VERSION 5.7 ;
  NOWIREEXTENSIONATPIN ON ;
  DIVIDERCHAR "/" ;
  BUSBITCHARS "[]" ;
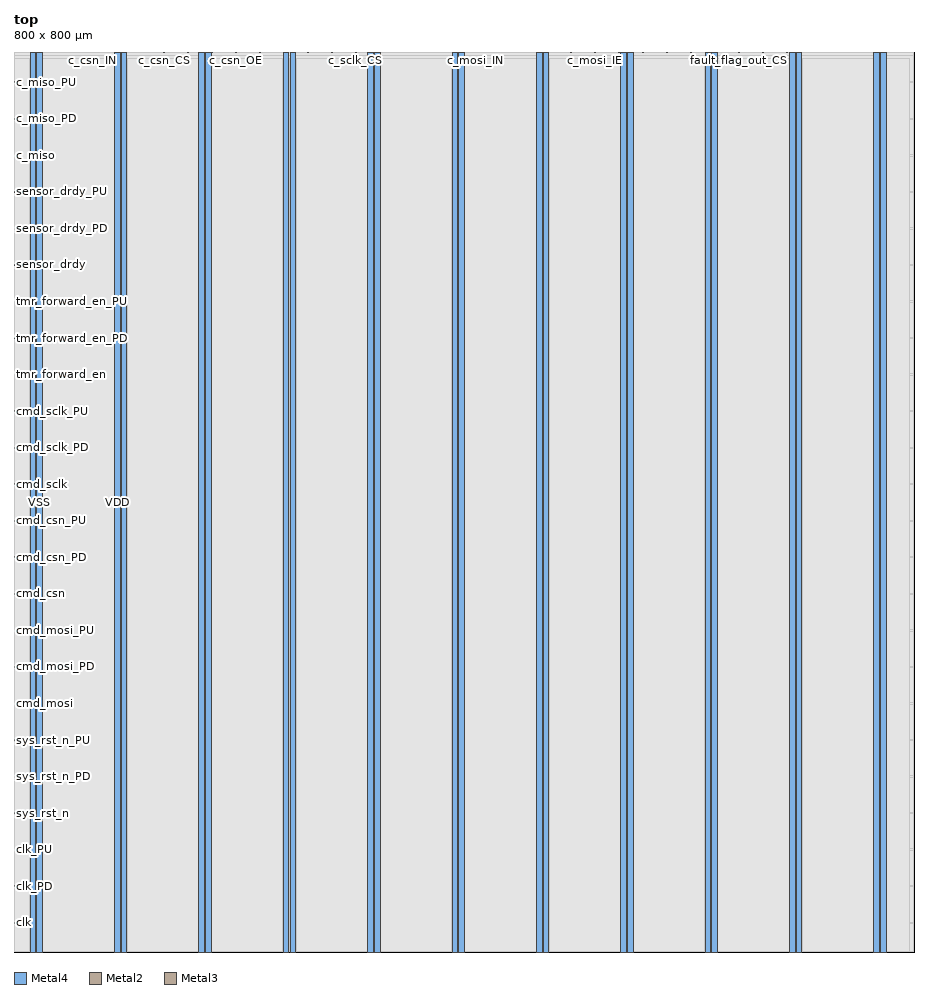
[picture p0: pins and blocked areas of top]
MACRO top
  CLASS BLOCK ;
  FOREIGN top ;
  ORIGIN 0.000 0.000 ;
  SIZE 800.000 BY 800.000 ;
  PIN VDD
    DIRECTION INOUT ;
    USE POWER ;
    PORT
      LAYER Metal4 ;
        RECT 14.380 0.000 19.380 800.000 ;
    END
    PORT
      LAYER Metal4 ;
        RECT 89.380 0.000 94.380 800.000 ;
    END
    PORT
      LAYER Metal4 ;
        RECT 164.380 0.000 169.380 800.000 ;
    END
    PORT
      LAYER Metal4 ;
        RECT 239.380 0.000 244.380 800.000 ;
    END
    PORT
      LAYER Metal4 ;
        RECT 314.380 0.000 319.380 800.000 ;
    END
    PORT
      LAYER Metal4 ;
        RECT 389.380 0.000 394.380 800.000 ;
    END
    PORT
      LAYER Metal4 ;
        RECT 464.380 0.000 469.380 800.000 ;
    END
    PORT
      LAYER Metal4 ;
        RECT 539.380 0.000 544.380 800.000 ;
    END
    PORT
      LAYER Metal4 ;
        RECT 614.380 0.000 619.380 800.000 ;
    END
    PORT
      LAYER Metal4 ;
        RECT 689.380 0.000 694.380 800.000 ;
    END
    PORT
      LAYER Metal4 ;
        RECT 764.380 0.000 769.380 800.000 ;
    END
  END VDD
  PIN VSS
    DIRECTION INOUT ;
    USE GROUND ;
    PORT
      LAYER Metal4 ;
        RECT 20.380 0.000 25.380 800.000 ;
    END
    PORT
      LAYER Metal4 ;
        RECT 95.380 0.000 100.380 800.000 ;
    END
    PORT
      LAYER Metal4 ;
        RECT 170.380 0.000 175.380 800.000 ;
    END
    PORT
      LAYER Metal4 ;
        RECT 245.380 0.000 250.380 800.000 ;
    END
    PORT
      LAYER Metal4 ;
        RECT 320.380 0.000 325.380 800.000 ;
    END
    PORT
      LAYER Metal4 ;
        RECT 395.380 0.000 400.380 800.000 ;
    END
    PORT
      LAYER Metal4 ;
        RECT 470.380 0.000 475.380 800.000 ;
    END
    PORT
      LAYER Metal4 ;
        RECT 545.380 0.000 550.380 800.000 ;
    END
    PORT
      LAYER Metal4 ;
        RECT 620.380 0.000 625.380 800.000 ;
    END
    PORT
      LAYER Metal4 ;
        RECT 695.380 0.000 700.380 800.000 ;
    END
    PORT
      LAYER Metal4 ;
        RECT 770.380 0.000 775.380 800.000 ;
    END
  END VSS
  PIN c_csn_CS
    DIRECTION OUTPUT ;
    USE SIGNAL ;
    ANTENNADIFFAREA 0.360800 ;
    PORT
      LAYER Metal2 ;
        RECT 133.280 799.440 133.840 800.000 ;
    END
  END c_csn_CS
  PIN c_csn_IE
    DIRECTION OUTPUT ;
    USE SIGNAL ;
    ANTENNADIFFAREA 0.360800 ;
    PORT
      LAYER Metal2 ;
        RECT 175.840 799.440 176.400 800.000 ;
    END
  END c_csn_IE
  PIN c_csn_IN
    DIRECTION INPUT ;
    USE SIGNAL ;
    PORT
      LAYER Metal2 ;
        RECT 69.440 799.440 70.000 800.000 ;
    END
  END c_csn_IN
  PIN c_csn_OE
    DIRECTION OUTPUT ;
    USE SIGNAL ;
    ANTENNADIFFAREA 0.536800 ;
    PORT
      LAYER Metal2 ;
        RECT 197.120 799.440 197.680 800.000 ;
    END
  END c_csn_OE
  PIN c_csn_OUT
    DIRECTION OUTPUT ;
    USE SIGNAL ;
    ANTENNADIFFAREA 0.897600 ;
    PORT
      LAYER Metal2 ;
        RECT 48.160 799.440 48.720 800.000 ;
    END
  END c_csn_OUT
  PIN c_csn_PD
    DIRECTION OUTPUT ;
    USE SIGNAL ;
    ANTENNADIFFAREA 0.360800 ;
    PORT
      LAYER Metal2 ;
        RECT 90.720 799.440 91.280 800.000 ;
    END
  END c_csn_PD
  PIN c_csn_PU
    DIRECTION OUTPUT ;
    USE SIGNAL ;
    ANTENNADIFFAREA 0.536800 ;
    PORT
      LAYER Metal2 ;
        RECT 112.000 799.440 112.560 800.000 ;
    END
  END c_csn_PU
  PIN c_csn_SL
    DIRECTION OUTPUT ;
    USE SIGNAL ;
    ANTENNADIFFAREA 0.360800 ;
    PORT
      LAYER Metal2 ;
        RECT 154.560 799.440 155.120 800.000 ;
    END
  END c_csn_SL
  PIN c_miso
    DIRECTION INPUT ;
    USE SIGNAL ;
    ANTENNAGATEAREA 0.396000 ;
    ANTENNADIFFAREA 0.410400 ;
    PORT
      LAYER Metal3 ;
        RECT 0.000 707.840 0.560 708.400 ;
    END
  END c_miso
  PIN c_miso_PD
    DIRECTION OUTPUT ;
    USE SIGNAL ;
    ANTENNADIFFAREA 0.360800 ;
    PORT
      LAYER Metal3 ;
        RECT 0.000 740.320 0.560 740.880 ;
    END
  END c_miso_PD
  PIN c_miso_PU
    DIRECTION OUTPUT ;
    USE SIGNAL ;
    ANTENNADIFFAREA 0.360800 ;
    PORT
      LAYER Metal3 ;
        RECT 0.000 772.800 0.560 773.360 ;
    END
  END c_miso_PU
  PIN c_mosi_CS
    DIRECTION OUTPUT ;
    USE SIGNAL ;
    ANTENNADIFFAREA 0.360800 ;
    PORT
      LAYER Metal2 ;
        RECT 473.760 799.440 474.320 800.000 ;
    END
  END c_mosi_CS
  PIN c_mosi_IE
    DIRECTION OUTPUT ;
    USE SIGNAL ;
    ANTENNADIFFAREA 0.360800 ;
    PORT
      LAYER Metal2 ;
        RECT 516.320 799.440 516.880 800.000 ;
    END
  END c_mosi_IE
  PIN c_mosi_IN
    DIRECTION INPUT ;
    USE SIGNAL ;
    PORT
      LAYER Metal2 ;
        RECT 409.920 799.440 410.480 800.000 ;
    END
  END c_mosi_IN
  PIN c_mosi_OE
    DIRECTION OUTPUT ;
    USE SIGNAL ;
    ANTENNADIFFAREA 0.536800 ;
    PORT
      LAYER Metal2 ;
        RECT 537.600 799.440 538.160 800.000 ;
    END
  END c_mosi_OE
  PIN c_mosi_OUT
    DIRECTION OUTPUT ;
    USE SIGNAL ;
    ANTENNADIFFAREA 0.897600 ;
    PORT
      LAYER Metal2 ;
        RECT 388.640 799.440 389.200 800.000 ;
    END
  END c_mosi_OUT
  PIN c_mosi_PD
    DIRECTION OUTPUT ;
    USE SIGNAL ;
    ANTENNADIFFAREA 0.360800 ;
    PORT
      LAYER Metal2 ;
        RECT 431.200 799.440 431.760 800.000 ;
    END
  END c_mosi_PD
  PIN c_mosi_PU
    DIRECTION OUTPUT ;
    USE SIGNAL ;
    ANTENNADIFFAREA 0.360800 ;
    PORT
      LAYER Metal2 ;
        RECT 452.480 799.440 453.040 800.000 ;
    END
  END c_mosi_PU
  PIN c_mosi_SL
    DIRECTION OUTPUT ;
    USE SIGNAL ;
    ANTENNADIFFAREA 0.360800 ;
    PORT
      LAYER Metal2 ;
        RECT 495.040 799.440 495.600 800.000 ;
    END
  END c_mosi_SL
  PIN c_sclk_CS
    DIRECTION OUTPUT ;
    USE SIGNAL ;
    ANTENNADIFFAREA 0.360800 ;
    PORT
      LAYER Metal2 ;
        RECT 303.520 799.440 304.080 800.000 ;
    END
  END c_sclk_CS
  PIN c_sclk_IE
    DIRECTION OUTPUT ;
    USE SIGNAL ;
    ANTENNADIFFAREA 0.360800 ;
    PORT
      LAYER Metal2 ;
        RECT 346.080 799.440 346.640 800.000 ;
    END
  END c_sclk_IE
  PIN c_sclk_IN
    DIRECTION INPUT ;
    USE SIGNAL ;
    PORT
      LAYER Metal2 ;
        RECT 239.680 799.440 240.240 800.000 ;
    END
  END c_sclk_IN
  PIN c_sclk_OE
    DIRECTION OUTPUT ;
    USE SIGNAL ;
    ANTENNADIFFAREA 0.536800 ;
    PORT
      LAYER Metal2 ;
        RECT 367.360 799.440 367.920 800.000 ;
    END
  END c_sclk_OE
  PIN c_sclk_OUT
    DIRECTION OUTPUT ;
    USE SIGNAL ;
    ANTENNADIFFAREA 0.897600 ;
    PORT
      LAYER Metal2 ;
        RECT 218.400 799.440 218.960 800.000 ;
    END
  END c_sclk_OUT
  PIN c_sclk_PD
    DIRECTION OUTPUT ;
    USE SIGNAL ;
    ANTENNADIFFAREA 0.360800 ;
    PORT
      LAYER Metal2 ;
        RECT 260.960 799.440 261.520 800.000 ;
    END
  END c_sclk_PD
  PIN c_sclk_PU
    DIRECTION OUTPUT ;
    USE SIGNAL ;
    ANTENNADIFFAREA 0.360800 ;
    PORT
      LAYER Metal2 ;
        RECT 282.240 799.440 282.800 800.000 ;
    END
  END c_sclk_PU
  PIN c_sclk_SL
    DIRECTION OUTPUT ;
    USE SIGNAL ;
    ANTENNADIFFAREA 0.360800 ;
    PORT
      LAYER Metal2 ;
        RECT 324.800 799.440 325.360 800.000 ;
    END
  END c_sclk_SL
  PIN clk
    DIRECTION INPUT ;
    USE SIGNAL ;
    ANTENNAGATEAREA 4.738000 ;
    ANTENNADIFFAREA 0.410400 ;
    PORT
      LAYER Metal3 ;
        RECT 0.000 25.760 0.560 26.320 ;
    END
  END clk
  PIN clk_PD
    DIRECTION OUTPUT ;
    USE SIGNAL ;
    ANTENNADIFFAREA 0.360800 ;
    PORT
      LAYER Metal3 ;
        RECT 0.000 58.240 0.560 58.800 ;
    END
  END clk_PD
  PIN clk_PU
    DIRECTION OUTPUT ;
    USE SIGNAL ;
    ANTENNADIFFAREA 0.360800 ;
    PORT
      LAYER Metal3 ;
        RECT 0.000 90.720 0.560 91.280 ;
    END
  END clk_PU
  PIN cmd_csn
    DIRECTION INPUT ;
    USE SIGNAL ;
    ANTENNAGATEAREA 0.396000 ;
    ANTENNADIFFAREA 0.410400 ;
    PORT
      LAYER Metal3 ;
        RECT 0.000 318.080 0.560 318.640 ;
    END
  END cmd_csn
  PIN cmd_csn_PD
    DIRECTION OUTPUT ;
    USE SIGNAL ;
    ANTENNADIFFAREA 0.360800 ;
    PORT
      LAYER Metal3 ;
        RECT 0.000 350.560 0.560 351.120 ;
    END
  END cmd_csn_PD
  PIN cmd_csn_PU
    DIRECTION OUTPUT ;
    USE SIGNAL ;
    ANTENNADIFFAREA 0.360800 ;
    PORT
      LAYER Metal3 ;
        RECT 0.000 383.040 0.560 383.600 ;
    END
  END cmd_csn_PU
  PIN cmd_mosi
    DIRECTION INPUT ;
    USE SIGNAL ;
    ANTENNAGATEAREA 0.396000 ;
    ANTENNADIFFAREA 0.410400 ;
    PORT
      LAYER Metal3 ;
        RECT 0.000 220.640 0.560 221.200 ;
    END
  END cmd_mosi
  PIN cmd_mosi_PD
    DIRECTION OUTPUT ;
    USE SIGNAL ;
    ANTENNADIFFAREA 0.360800 ;
    PORT
      LAYER Metal3 ;
        RECT 0.000 253.120 0.560 253.680 ;
    END
  END cmd_mosi_PD
  PIN cmd_mosi_PU
    DIRECTION OUTPUT ;
    USE SIGNAL ;
    ANTENNADIFFAREA 0.360800 ;
    PORT
      LAYER Metal3 ;
        RECT 0.000 285.600 0.560 286.160 ;
    END
  END cmd_mosi_PU
  PIN cmd_sclk
    DIRECTION INPUT ;
    USE SIGNAL ;
    ANTENNAGATEAREA 0.396000 ;
    ANTENNADIFFAREA 0.410400 ;
    PORT
      LAYER Metal3 ;
        RECT 0.000 415.520 0.560 416.080 ;
    END
  END cmd_sclk
  PIN cmd_sclk_PD
    DIRECTION OUTPUT ;
    USE SIGNAL ;
    ANTENNADIFFAREA 0.360800 ;
    PORT
      LAYER Metal3 ;
        RECT 0.000 448.000 0.560 448.560 ;
    END
  END cmd_sclk_PD
  PIN cmd_sclk_PU
    DIRECTION OUTPUT ;
    USE SIGNAL ;
    ANTENNADIFFAREA 0.360800 ;
    PORT
      LAYER Metal3 ;
        RECT 0.000 480.480 0.560 481.040 ;
    END
  END cmd_sclk_PU
  PIN fault_flag_out_CS
    DIRECTION OUTPUT ;
    USE SIGNAL ;
    ANTENNADIFFAREA 0.360800 ;
    PORT
      LAYER Metal2 ;
        RECT 644.000 799.440 644.560 800.000 ;
    END
  END fault_flag_out_CS
  PIN fault_flag_out_IE
    DIRECTION OUTPUT ;
    USE SIGNAL ;
    ANTENNADIFFAREA 0.360800 ;
    PORT
      LAYER Metal2 ;
        RECT 686.560 799.440 687.120 800.000 ;
    END
  END fault_flag_out_IE
  PIN fault_flag_out_IN
    DIRECTION INPUT ;
    USE SIGNAL ;
    PORT
      LAYER Metal2 ;
        RECT 580.160 799.440 580.720 800.000 ;
    END
  END fault_flag_out_IN
  PIN fault_flag_out_OE
    DIRECTION OUTPUT ;
    USE SIGNAL ;
    ANTENNADIFFAREA 0.536800 ;
    PORT
      LAYER Metal2 ;
        RECT 707.840 799.440 708.400 800.000 ;
    END
  END fault_flag_out_OE
  PIN fault_flag_out_OUT
    DIRECTION OUTPUT ;
    USE SIGNAL ;
    ANTENNADIFFAREA 0.897600 ;
    PORT
      LAYER Metal2 ;
        RECT 558.880 799.440 559.440 800.000 ;
    END
  END fault_flag_out_OUT
  PIN fault_flag_out_PD
    DIRECTION OUTPUT ;
    USE SIGNAL ;
    ANTENNADIFFAREA 0.360800 ;
    PORT
      LAYER Metal2 ;
        RECT 601.440 799.440 602.000 800.000 ;
    END
  END fault_flag_out_PD
  PIN fault_flag_out_PU
    DIRECTION OUTPUT ;
    USE SIGNAL ;
    ANTENNADIFFAREA 0.360800 ;
    PORT
      LAYER Metal2 ;
        RECT 622.720 799.440 623.280 800.000 ;
    END
  END fault_flag_out_PU
  PIN fault_flag_out_SL
    DIRECTION OUTPUT ;
    USE SIGNAL ;
    ANTENNADIFFAREA 0.360800 ;
    PORT
      LAYER Metal2 ;
        RECT 665.280 799.440 665.840 800.000 ;
    END
  END fault_flag_out_SL
  PIN sensor_drdy
    DIRECTION INPUT ;
    USE SIGNAL ;
    ANTENNAGATEAREA 0.396000 ;
    ANTENNADIFFAREA 0.410400 ;
    PORT
      LAYER Metal3 ;
        RECT 0.000 610.400 0.560 610.960 ;
    END
  END sensor_drdy
  PIN sensor_drdy_PD
    DIRECTION OUTPUT ;
    USE SIGNAL ;
    ANTENNADIFFAREA 0.360800 ;
    PORT
      LAYER Metal3 ;
        RECT 0.000 642.880 0.560 643.440 ;
    END
  END sensor_drdy_PD
  PIN sensor_drdy_PU
    DIRECTION OUTPUT ;
    USE SIGNAL ;
    ANTENNADIFFAREA 0.360800 ;
    PORT
      LAYER Metal3 ;
        RECT 0.000 675.360 0.560 675.920 ;
    END
  END sensor_drdy_PU
  PIN sys_rst_n
    DIRECTION INPUT ;
    USE SIGNAL ;
    ANTENNAGATEAREA 0.396000 ;
    ANTENNADIFFAREA 0.410400 ;
    PORT
      LAYER Metal3 ;
        RECT 0.000 123.200 0.560 123.760 ;
    END
  END sys_rst_n
  PIN sys_rst_n_PD
    DIRECTION OUTPUT ;
    USE SIGNAL ;
    ANTENNADIFFAREA 0.360800 ;
    PORT
      LAYER Metal3 ;
        RECT 0.000 155.680 0.560 156.240 ;
    END
  END sys_rst_n_PD
  PIN sys_rst_n_PU
    DIRECTION OUTPUT ;
    USE SIGNAL ;
    ANTENNADIFFAREA 0.360800 ;
    PORT
      LAYER Metal3 ;
        RECT 0.000 188.160 0.560 188.720 ;
    END
  END sys_rst_n_PU
  PIN tmr_forward_en
    DIRECTION INPUT ;
    USE SIGNAL ;
    ANTENNAGATEAREA 0.396000 ;
    ANTENNADIFFAREA 0.410400 ;
    PORT
      LAYER Metal3 ;
        RECT 0.000 512.960 0.560 513.520 ;
    END
  END tmr_forward_en
  PIN tmr_forward_en_PD
    DIRECTION OUTPUT ;
    USE SIGNAL ;
    ANTENNADIFFAREA 0.360800 ;
    PORT
      LAYER Metal3 ;
        RECT 0.000 545.440 0.560 546.000 ;
    END
  END tmr_forward_en_PD
  PIN tmr_forward_en_PU
    DIRECTION OUTPUT ;
    USE SIGNAL ;
    ANTENNADIFFAREA 0.360800 ;
    PORT
      LAYER Metal3 ;
        RECT 0.000 577.920 0.560 578.480 ;
    END
  END tmr_forward_en_PU
  OBS
      LAYER Nwell ;
        RECT 0.130 3.490 799.550 796.190 ;
      LAYER Metal1 ;
        RECT 0.560 3.620 799.120 796.060 ;
      LAYER Metal2 ;
        RECT 0.140 799.140 47.860 799.860 ;
        RECT 49.020 799.140 69.140 799.860 ;
        RECT 70.300 799.140 90.420 799.860 ;
        RECT 91.580 799.140 111.700 799.860 ;
        RECT 112.860 799.140 132.980 799.860 ;
        RECT 134.140 799.140 154.260 799.860 ;
        RECT 155.420 799.140 175.540 799.860 ;
        RECT 176.700 799.140 196.820 799.860 ;
        RECT 197.980 799.140 218.100 799.860 ;
        RECT 219.260 799.140 239.380 799.860 ;
        RECT 240.540 799.140 260.660 799.860 ;
        RECT 261.820 799.140 281.940 799.860 ;
        RECT 283.100 799.140 303.220 799.860 ;
        RECT 304.380 799.140 324.500 799.860 ;
        RECT 325.660 799.140 345.780 799.860 ;
        RECT 346.940 799.140 367.060 799.860 ;
        RECT 368.220 799.140 388.340 799.860 ;
        RECT 389.500 799.140 409.620 799.860 ;
        RECT 410.780 799.140 430.900 799.860 ;
        RECT 432.060 799.140 452.180 799.860 ;
        RECT 453.340 799.140 473.460 799.860 ;
        RECT 474.620 799.140 494.740 799.860 ;
        RECT 495.900 799.140 516.020 799.860 ;
        RECT 517.180 799.140 537.300 799.860 ;
        RECT 538.460 799.140 558.580 799.860 ;
        RECT 559.740 799.140 579.860 799.860 ;
        RECT 581.020 799.140 601.140 799.860 ;
        RECT 602.300 799.140 622.420 799.860 ;
        RECT 623.580 799.140 643.700 799.860 ;
        RECT 644.860 799.140 664.980 799.860 ;
        RECT 666.140 799.140 686.260 799.860 ;
        RECT 687.420 799.140 707.540 799.860 ;
        RECT 708.700 799.140 799.540 799.860 ;
        RECT 0.140 0.090 799.540 799.140 ;
      LAYER Metal3 ;
        RECT 0.090 773.660 799.590 797.300 ;
        RECT 0.860 772.500 799.590 773.660 ;
        RECT 0.090 741.180 799.590 772.500 ;
        RECT 0.860 740.020 799.590 741.180 ;
        RECT 0.090 708.700 799.590 740.020 ;
        RECT 0.860 707.540 799.590 708.700 ;
        RECT 0.090 676.220 799.590 707.540 ;
        RECT 0.860 675.060 799.590 676.220 ;
        RECT 0.090 643.740 799.590 675.060 ;
        RECT 0.860 642.580 799.590 643.740 ;
        RECT 0.090 611.260 799.590 642.580 ;
        RECT 0.860 610.100 799.590 611.260 ;
        RECT 0.090 578.780 799.590 610.100 ;
        RECT 0.860 577.620 799.590 578.780 ;
        RECT 0.090 546.300 799.590 577.620 ;
        RECT 0.860 545.140 799.590 546.300 ;
        RECT 0.090 513.820 799.590 545.140 ;
        RECT 0.860 512.660 799.590 513.820 ;
        RECT 0.090 481.340 799.590 512.660 ;
        RECT 0.860 480.180 799.590 481.340 ;
        RECT 0.090 448.860 799.590 480.180 ;
        RECT 0.860 447.700 799.590 448.860 ;
        RECT 0.090 416.380 799.590 447.700 ;
        RECT 0.860 415.220 799.590 416.380 ;
        RECT 0.090 383.900 799.590 415.220 ;
        RECT 0.860 382.740 799.590 383.900 ;
        RECT 0.090 351.420 799.590 382.740 ;
        RECT 0.860 350.260 799.590 351.420 ;
        RECT 0.090 318.940 799.590 350.260 ;
        RECT 0.860 317.780 799.590 318.940 ;
        RECT 0.090 286.460 799.590 317.780 ;
        RECT 0.860 285.300 799.590 286.460 ;
        RECT 0.090 253.980 799.590 285.300 ;
        RECT 0.860 252.820 799.590 253.980 ;
        RECT 0.090 221.500 799.590 252.820 ;
        RECT 0.860 220.340 799.590 221.500 ;
        RECT 0.090 189.020 799.590 220.340 ;
        RECT 0.860 187.860 799.590 189.020 ;
        RECT 0.090 156.540 799.590 187.860 ;
        RECT 0.860 155.380 799.590 156.540 ;
        RECT 0.090 124.060 799.590 155.380 ;
        RECT 0.860 122.900 799.590 124.060 ;
        RECT 0.090 91.580 799.590 122.900 ;
        RECT 0.860 90.420 799.590 91.580 ;
        RECT 0.090 59.100 799.590 90.420 ;
        RECT 0.860 57.940 799.590 59.100 ;
        RECT 0.090 26.620 799.590 57.940 ;
        RECT 0.860 25.460 799.590 26.620 ;
        RECT 0.090 0.140 799.590 25.460 ;
      LAYER Metal4 ;
        RECT 0.700 0.650 14.080 794.550 ;
        RECT 19.680 0.650 20.080 794.550 ;
        RECT 25.680 0.650 89.080 794.550 ;
        RECT 94.680 0.650 95.080 794.550 ;
        RECT 100.680 0.650 164.080 794.550 ;
        RECT 169.680 0.650 170.080 794.550 ;
        RECT 175.680 0.650 239.080 794.550 ;
        RECT 244.680 0.650 245.080 794.550 ;
        RECT 250.680 0.650 314.080 794.550 ;
        RECT 319.680 0.650 320.080 794.550 ;
        RECT 325.680 0.650 389.080 794.550 ;
        RECT 394.680 0.650 395.080 794.550 ;
        RECT 400.680 0.650 464.080 794.550 ;
        RECT 469.680 0.650 470.080 794.550 ;
        RECT 475.680 0.650 539.080 794.550 ;
        RECT 544.680 0.650 545.080 794.550 ;
        RECT 550.680 0.650 614.080 794.550 ;
        RECT 619.680 0.650 620.080 794.550 ;
        RECT 625.680 0.650 689.080 794.550 ;
        RECT 694.680 0.650 695.080 794.550 ;
        RECT 700.680 0.650 764.080 794.550 ;
        RECT 769.680 0.650 770.080 794.550 ;
        RECT 775.680 0.650 796.180 794.550 ;
  END
END top
END LIBRARY

